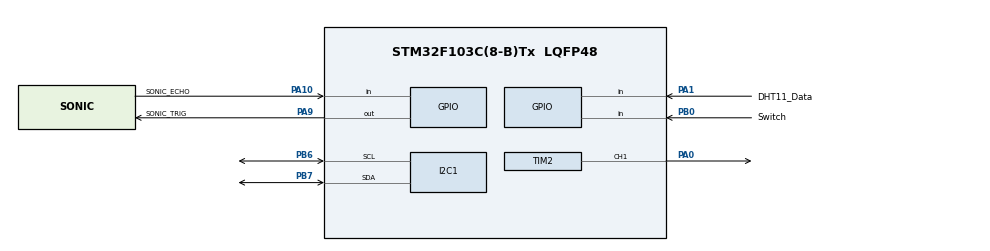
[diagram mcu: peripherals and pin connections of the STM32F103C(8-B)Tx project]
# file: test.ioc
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Mcu.Family=STM32F1
Mcu.Name=STM32F103C(8-B)Tx
Mcu.Package=LQFP48
NVIC.PriorityGroup=NVIC_PRIORITYGROUP_4
PA0-WKUP.Signal=S_TIM2_CH1_ETR
PA1.GPIO_Label=DHT11_Data
PA1.GPIO_PuPd=GPIO_PULLUP
PA1.Signal=GPIO_Input
PA10.GPIO_Label=SONIC_ECHO
PA10.Signal=GPIO_Input
PA13.Mode=Serial_Wire
PA13.Signal=SYS_JTMS-SWDIO
PA14.Mode=Serial_Wire
PA14.Signal=SYS_JTCK-SWCLK
PA9.GPIO_Label=SONIC_TRIG
PA9.Signal=GPIO_Output
PB0.GPIO_Label=Switch
PB0.GPIO_PuPd=GPIO_PULLUP
PB0.Signal=GPIO_Input
PB6.Mode=I2C
PB6.Signal=I2C1_SCL
PB7.Mode=I2C
PB7.Signal=I2C1_SDA
ProjectManager.HeapSize=0x200
ProjectManager.StackSize=0x400
ProjectManager.TargetToolchain=STM32CubeIDE
RCC.AHBFreq_Value=64000000
RCC.APB1CLKDivider=RCC_HCLK_DIV2
RCC.APB1Freq_Value=32000000
RCC.APB1TimFreq_Value=64000000
RCC.APB2Freq_Value=64000000
RCC.APB2TimFreq_Value=64000000
RCC.HCLKFreq_Value=64000000
RCC.PLLMUL=RCC_PLL_MUL16
RCC.SYSCLKFreq_VALUE=64000000
RCC.SYSCLKSource=RCC_SYSCLKSOURCE_PLLCLK
RCC.USBFreq_Value=64000000
SH.S_TIM2_CH1_ETR.0=TIM2_CH1,PWM Generation1 CH1
TIM2.Channel-PWM\ Generation1\ CH1=TIM_CHANNEL_1
TIM2.Period=19999
TIM2.Prescaler=71
VP_TIM2_VS_ClockSourceINT.Mode=Internal
board=custom

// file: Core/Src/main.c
/* USER CODE BEGIN Header */
/**
  ******************************************************************************
  * @file           : main.c
  * @brief          : Main program body - Servo Motor, DHT11, Ultrasonic Sensor & LCD
  ******************************************************************************
  * Hardware Connections:
  * LCD: B6 (RS), B7 (E) - as per your existing setup
  * Servo Motor: A0 (PWM) - Used as indicator based on temperature/distance
  * DHT11: A1 (Data pin)
  * Ultrasonic HC-SR04:
  *   - Trigger: A9 (GPIO Output)
  *   - Echo: A10 (GPIO Input with interrupt capability)
  * Keypad 3x4: A2-A8 (keep connected but not used)
  *
  * 2-Position Switch:
  * One pin → B0 (STM32 GPIO with internal pull-up)
  * Other pin → GND
  *
  * Switch Logic:
  * Position 1 (Released/Pull): B0 = HIGH → DHT11 Temperature Mode
  * Position 2 (Pressed/Push): B0 = LOW  → Ultrasonic Distance Mode
  *
  * Motor Control Logic:
  * - Temperature ≥ 30°C: Motor runs (indicator ON)
  * - Distance ≤ 20cm: Motor runs (indicator ON)
  * - Otherwise: Motor stopped (indicator OFF)
  ******************************************************************************
  */
/* USER CODE END Header */

#include "main.h"

/* USER CODE BEGIN Includes */
#include "i2c-lcd.h"
#include "sg90.h"
#include "dht11.h"
#include "switch.h"
#include "sonic.h"  // Ultrasonic sensor header
#include "stdio.h"
/* USER CODE END Includes */

/* USER CODE BEGIN PD */
#define TEMP_THRESHOLD 30.0     // Temperature threshold in Celsius
#define DISTANCE_THRESHOLD 20.0 // Distance threshold in cm
/* USER CODE END PD */

I2C_HandleTypeDef hi2c1;
TIM_HandleTypeDef htim2;

/* USER CODE BEGIN PV */
uint8_t motor_status = 0; // 0 = stopped, 1 = running
uint8_t current_mode = 1; // Start with DHT11 mode (switch released)
uint8_t previous_mode = 1;
uint32_t mode_change_time = 0;

// Sensor data variables
DHT11_Data_t dht11_data = {0};
float distance = 0.0;

// Motor control variables
uint8_t motor_active_temp = 0;     // Motor active due to temperature
uint8_t motor_active_distance = 0; // Motor active due to distance
uint8_t last_motor_state = 0;      // Previous motor state for change detection

static uint8_t temp_first = 1, distance_first = 1;
/* USER CODE END PV */

void SystemClock_Config(void);
static void MX_GPIO_Init(void);
static void MX_I2C1_Init(void);
static void MX_TIM2_Init(void);
/* USER CODE BEGIN PFP */
// Application Functions
void Display_Temperature_Mode(void);
void Display_Distance_Mode(void);
void Motor_Control_Logic(void);
void Update_Motor_Status(void);
/* USER CODE END PFP */

/* USER CODE BEGIN 0 */

/**
 * @brief Motor control logic based on temperature and distance thresholds
 * Only considers readings from the currently active mode
 */
void Motor_Control_Logic(void)
{
    // Reset motor activation flags
    motor_active_temp = 0;
    motor_active_distance = 0;

    // Only check temperature if we're in temperature mode (mode 1)
    if (current_mode == 1)
    {
        if (dht11_data.valid && dht11_data.temperature >= TEMP_THRESHOLD)
        {
            motor_active_temp = 1;
        }
    }

    // Only check distance if we're in distance mode (mode 2)
    if (current_mode == 2)
    {
        if (distance > 0 && distance <= DISTANCE_THRESHOLD)
        {
            motor_active_distance = 1;
        }
    }

    // Update overall motor status
    motor_status = (motor_active_temp || motor_active_distance) ? 1 : 0;
}

/**
 * @brief Update motor physical state based on motor_status
 */
void Update_Motor_Status(void)
{
    if (motor_status != last_motor_state)
    {
        if (motor_status)
        {
            // Start motor - sweep motion for indication
            SG90_Start_Sweep();
        }
        else
        {
            // Stop motor - return to center position
            SG90_Stop();
        }
        last_motor_state = motor_status;
    }

    // Continue sweep motion if motor is active
    if (motor_status)
    {
        SG90_Update_Sweep();
    }
}

/**
 * @brief Display temperature mode with DHT11 readings and motor status
 */
void Display_Temperature_Mode(void)
{
    static uint32_t last_update = 0;
    static uint8_t first_run = 1;

    // Show mode change message once
    if (temp_first)
    {
        lcd_clear();
        lcd_put_cur(0, 0);
        lcd_send_string("DHT11 Mode      ");
        lcd_put_cur(1, 0);
        lcd_send_string("Reading...      ");
        HAL_Delay(1000);
        temp_first = 0;
        first_run = 1;
    }

    // Update DHT11 data every 2 seconds
    if (HAL_GetTick() - last_update > 2000)
    {
        DHT11_Read_Data(&dht11_data);
        last_update = HAL_GetTick();
        first_run = 1;
    }

    // Display temperature and motor status
    if (first_run)
    {
        if (dht11_data.valid)
        {
            char temp_str[17];
            char status_str[17];

            int temp_int = (int)dht11_data.temperature;
            int temp_dec = (int)((dht11_data.temperature - temp_int) * 10);

            sprintf(temp_str, "T:%d.%dC", temp_int, temp_dec);

            // Add motor status and threshold info
            if (motor_active_temp)
            {
                sprintf(status_str, "%s M:ON(T>=30)", temp_str);
            }
            else
            {
                sprintf(status_str, "%s M:OFF     ", temp_str);
            }

            lcd_put_cur(0, 0);
            lcd_send_string(status_str);

            // Second line: Humidity and overall motor status
            int hum_int = (int)dht11_data.humidity;
            int hum_dec = (int)((dht11_data.humidity - hum_int) * 10);

            char hum_str[17];
            sprintf(hum_str, "H:%d.%d%% Motor:%s ", hum_int, hum_dec, motor_status ? "ON " : "OFF");

            lcd_put_cur(1, 0);
            lcd_send_string(hum_str);
        }
        else
        {
            lcd_put_cur(0, 0);
            lcd_send_string("DHT11 Error     ");
            lcd_put_cur(1, 0);
            lcd_send_string("Check Wiring    ");
        }
        first_run = 0;
    }
}

/**
 * @brief Display distance mode with ultrasonic readings and motor status
 */
void Display_Distance_Mode(void)
{
    static uint32_t last_update = 0;
    static uint8_t first_run = 1;

    // Show mode change message once
    if (distance_first)
    {
        lcd_clear();
        lcd_put_cur(0, 0);
        lcd_send_string("Distance Mode   ");
        lcd_put_cur(1, 0);
        lcd_send_string("Measuring...    ");
        HAL_Delay(1000);
        distance_first = 0;
        first_run = 1;
    }

    // Update distance data every 500ms
    if (HAL_GetTick() - last_update > 500)
    {
        distance = SONIC_Read_Distance();
        last_update = HAL_GetTick();
        first_run = 1;
    }

    // Display distance and motor status
    if (first_run)
    {
        char dist_str[17];
        char status_str[17];

        if (distance > 0)
        {
            int dist_int = (int)distance;
            int dist_dec = (int)((distance - dist_int) * 10);

            sprintf(dist_str, "D:%d.%dcm", dist_int, dist_dec);

            // Add motor status and threshold info
            if (motor_active_distance)
            {
                sprintf(status_str, "%s M:ON(<=20)", dist_str);
            }
            else
            {
                sprintf(status_str, "%s M:OFF     ", dist_str);
            }
        }
        else
        {
            sprintf(status_str, "D:Error M:OFF   ");
        }

        lcd_put_cur(0, 0);
        lcd_send_string(status_str);

        // Second line: Overall motor status and threshold info
        char motor_str[17];
        sprintf(motor_str, "Motor: %s      ", motor_status ? "ACTIVE  " : "STOPPED ");

        lcd_put_cur(1, 0);
        lcd_send_string(motor_str);

        first_run = 0;
    }
}

/* USER CODE END 0 */

int main(void)
{

  /* MCU Configuration--------------------------------------------------------*/

  /* Reset of all peripherals, Initializes the Flash interface and the Systick. */
  HAL_Init();

  /* Configure the system clock */
  SystemClock_Config();

  /* Initialize all configured peripherals */
  MX_GPIO_Init();
  MX_I2C1_Init();
  MX_TIM2_Init();

  // Enable DWT cycle counter (for microsecond delays)
  CoreDebug->DEMCR |= CoreDebug_DEMCR_TRCENA_Msk;
  DWT->CTRL |= DWT_CTRL_CYCCNTENA_Msk;
  /* USER CODE BEGIN 2 */

  // Initialize LCD Display
  lcd_init();

  // Show startup message
  lcd_clear();
  lcd_put_cur(0, 0);
  lcd_send_string("System Ready    ");
  lcd_put_cur(1, 0);
  lcd_send_string("T>=30C|D<=20cm  ");
  HAL_Delay(2000);

  // Initialize SG90 Servo Motor
  SG90_Init();

  // Initialize DHT11 Sensor
  DHT11_Init();

  // Initialize Ultrasonic Sensor
  SONIC_Init();

  // Initialize Switch
  Switch_Init();

  // Clear screen for operation
  lcd_clear();

  /* USER CODE END 2 */

  /* Infinite loop */
  while (1)
  {

    /* USER CODE BEGIN 3 */

    // Read current switch state
    uint8_t switch_mode = Switch_Read_Mode();

    // Check for mode change with debouncing
    if (switch_mode != previous_mode)
    {
        if (HAL_GetTick() - mode_change_time > 300) // 300ms debounce
        {
            current_mode = switch_mode;
            previous_mode = switch_mode;
            mode_change_time = HAL_GetTick();

            // Reset first_run flags for clean mode transition
            if (current_mode == 1)
            {
                temp_first = 1;
            }
            if (current_mode == 2)
            {
                distance_first = 1;
            }

            // Force immediate motor control update for new mode
            Motor_Control_Logic();
        }
    }

    // Update motor status regardless of current display mode
    Update_Motor_Status();

    // Execute current display mode
    switch (current_mode)
    {
        case 1: // DHT11 Temperature mode (switch released/HIGH)
            Display_Temperature_Mode();

            // Update motor control logic only for temperature mode
            Motor_Control_Logic();
            HAL_Delay(100);
            break;

        case 2: // Ultrasonic Distance mode (switch pressed/LOW)
            Display_Distance_Mode();

            // Update motor control logic only for distance mode
            Motor_Control_Logic();
            HAL_Delay(100);
            break;

        default:
            // Default to DHT11 mode
            current_mode = 1;
            break;
    }

  }
  /* USER CODE END 3 */
}

void SystemClock_Config(void)
{
  RCC_OscInitTypeDef RCC_OscInitStruct = {0};
  RCC_ClkInitTypeDef RCC_ClkInitStruct = {0};

  /** Initializes the RCC Oscillators according to the specified parameters
  * in the RCC_OscInitStruct structure.
  */
  RCC_OscInitStruct.OscillatorType = RCC_OSCILLATORTYPE_HSE;
  RCC_OscInitStruct.HSEState = RCC_HSE_ON;
  RCC_OscInitStruct.HSEPredivValue = RCC_HSE_PREDIV_DIV1;
  RCC_OscInitStruct.HSIState = RCC_HSI_ON;
  RCC_OscInitStruct.PLL.PLLState = RCC_PLL_ON;
  RCC_OscInitStruct.PLL.PLLSource = RCC_PLLSOURCE_HSE;
  RCC_OscInitStruct.PLL.PLLMUL = RCC_PLL_MUL9;
  if (HAL_RCC_OscConfig(&RCC_OscInitStruct) != HAL_OK)
  {
    Error_Handler();
  }

  /** Initializes the CPU, AHB and APB buses clocks
  */
  RCC_ClkInitStruct.ClockType = RCC_CLOCKTYPE_HCLK|RCC_CLOCKTYPE_SYSCLK
                              |RCC_CLOCKTYPE_PCLK1|RCC_CLOCKTYPE_PCLK2;
  RCC_ClkInitStruct.SYSCLKSource = RCC_SYSCLKSOURCE_PLLCLK;
  RCC_ClkInitStruct.AHBCLKDivider = RCC_SYSCLK_DIV1;
  RCC_ClkInitStruct.APB1CLKDivider = RCC_HCLK_DIV2;
  RCC_ClkInitStruct.APB2CLKDivider = RCC_HCLK_DIV1;

  if (HAL_RCC_ClockConfig(&RCC_ClkInitStruct, FLASH_LATENCY_2) != HAL_OK)
  {
    Error_Handler();
  }
}

static void MX_TIM2_Init(void)
{

  TIM_ClockConfigTypeDef sClockSourceConfig = {0};
  TIM_MasterConfigTypeDef sMasterConfig = {0};
  TIM_OC_InitTypeDef sConfigOC = {0};

  htim2.Instance = TIM2;
  htim2.Init.Prescaler = 71;  // 72MHz / (71+1) = 1MHz (1us per tick)
  htim2.Init.CounterMode = TIM_COUNTERMODE_UP;
  htim2.Init.Period = 19999;  // 20ms period for servo
  htim2.Init.ClockDivision = TIM_CLOCKDIVISION_DIV1;
  htim2.Init.AutoReloadPreload = TIM_AUTORELOAD_PRELOAD_DISABLE;
  if (HAL_TIM_Base_Init(&htim2) != HAL_OK)
  {
    Error_Handler();
  }
  sClockSourceConfig.ClockSource = TIM_CLOCKSOURCE_INTERNAL;
  if (HAL_TIM_ConfigClockSource(&htim2, &sClockSourceConfig) != HAL_OK)
  {
    Error_Handler();
  }
  if (HAL_TIM_PWM_Init(&htim2) != HAL_OK)
  {
    Error_Handler();
  }
  sMasterConfig.MasterOutputTrigger = TIM_TRGO_RESET;
  sMasterConfig.MasterSlaveMode = TIM_MASTERSLAVEMODE_DISABLE;
  if (HAL_TIMEx_MasterConfigSynchronization(&htim2, &sMasterConfig) != HAL_OK)
  {
    Error_Handler();
  }
  sConfigOC.OCMode = TIM_OCMODE_PWM1;
  sConfigOC.Pulse = 1500;  // Initial pulse width (90 degrees)
  sConfigOC.OCPolarity = TIM_OCPOLARITY_HIGH;
  sConfigOC.OCFastMode = TIM_OCFAST_DISABLE;
  if (HAL_TIM_PWM_ConfigChannel(&htim2, &sConfigOC, TIM_CHANNEL_1) != HAL_OK)
  {
    Error_Handler();
  }
  HAL_TIM_MspPostInit(&htim2);

}

static void MX_I2C1_Init(void)
{

  hi2c1.Instance = I2C1;
  hi2c1.Init.ClockSpeed = 100000;
  hi2c1.Init.DutyCycle = I2C_DUTYCYCLE_2;
  hi2c1.Init.OwnAddress1 = 0;
  hi2c1.Init.AddressingMode = I2C_ADDRESSINGMODE_7BIT;
  hi2c1.Init.DualAddressMode = I2C_DUALADDRESS_DISABLE;
  hi2c1.Init.OwnAddress2 = 0;
  hi2c1.Init.GeneralCallMode = I2C_GENERALCALL_DISABLE;
  hi2c1.Init.NoStretchMode = I2C_NOSTRETCH_DISABLE;
  if (HAL_I2C_Init(&hi2c1) != HAL_OK)
  {
    Error_Handler();
  }

}

static void MX_GPIO_Init(void)
{

  /* GPIO Ports Clock Enable */
  __HAL_RCC_GPIOD_CLK_ENABLE();
  __HAL_RCC_GPIOA_CLK_ENABLE();
  __HAL_RCC_GPIOB_CLK_ENABLE();

  /* Switch, DHT11, and Ultrasonic GPIO pins initialized in their respective Init() functions */

}

void Error_Handler(void)
{
  __disable_irq();
  while (1)
  {
  }
}
